VERSION 5.8 ;
BUSBITCHARS "[]" ;
DIVIDERCHAR "/" ;

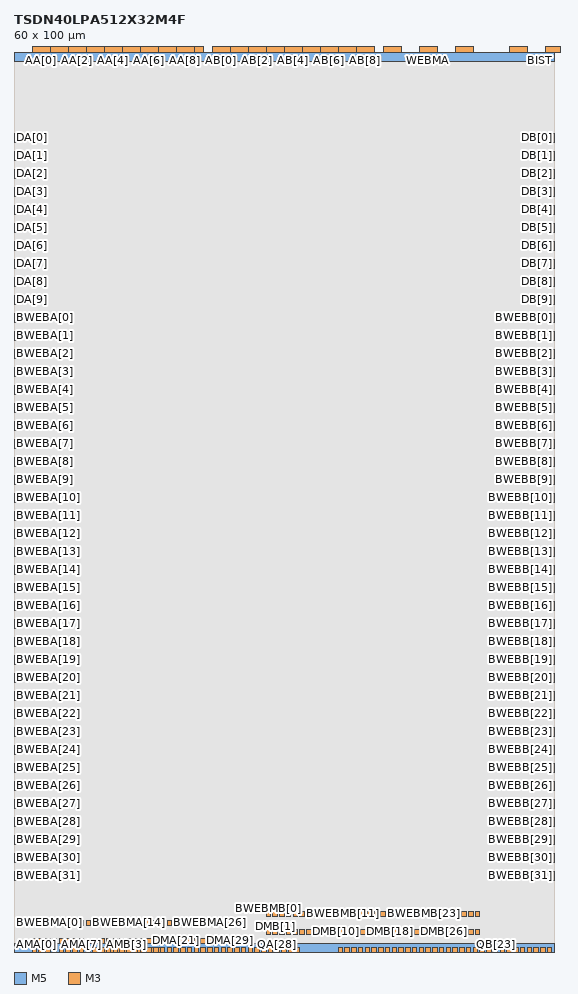
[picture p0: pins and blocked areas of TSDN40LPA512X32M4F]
MACRO TSDN40LPA512X32M4F
  CLASS BLOCK ;
  ORIGIN 0 0 ;
  SIZE 60.0 BY 100.0 ;        # TODO: pick conservative size (microns)
  SITE core ;                 # TODO: stdcell site name from your PDK
  SYMMETRY X Y ;

  # ------- Power/Ground pins (required) -------
  PIN VDD
    DIRECTION INOUT ; USE POWER ;
    PORT
      LAYER M5 ;               # TODO: PG routing layer
        RECT 0 99 60 100 ;
    END
  END VDD
  PIN VSS
    DIRECTION INOUT ; USE GROUND ;
    PORT
      LAYER M5 ;
        RECT 0 0 60 1 ;
    END
  END VSS

  # ------- Scalar control/clock pins (examples packed along the north edge) -------
  PIN CLKA  DIRECTION INPUT ; USE SIGNAL ;
    PORT LAYER M3 ; RECT  5 100  7 102 ; END
  END CLKA
  PIN CLKB  DIRECTION INPUT ; USE SIGNAL ;
    PORT LAYER M3 ; RECT  9 100 11 102 ; END
  END CLKB
  PIN CLKM  DIRECTION INPUT ; USE SIGNAL ;
    PORT LAYER M3 ; RECT 13 100 15 102 ; END
  END CLKM

  PIN CEBA  DIRECTION INPUT ; USE SIGNAL ;
    PORT LAYER M3 ; RECT 19 100 21 102 ; END
  END CEBA
  PIN CEBB  DIRECTION INPUT ; USE SIGNAL ;
    PORT LAYER M3 ; RECT 23 100 25 102 ; END
  END CEBB
  PIN CEBMA DIRECTION INPUT ; USE SIGNAL ;
    PORT LAYER M3 ; RECT 27 100 29 102 ; END
  END CEBMA
  PIN CEBMB DIRECTION INPUT ; USE SIGNAL ;
    PORT LAYER M3 ; RECT 31 100 33 102 ; END
  END CEBMB

  PIN WEBA  DIRECTION INPUT ; USE SIGNAL ;
    PORT LAYER M3 ; RECT 37 100 39 102 ; END
  END WEBA
  PIN WEBB  DIRECTION INPUT ; USE SIGNAL ;
    PORT LAYER M3 ; RECT 41 100 43 102 ; END
  END WEBB
  PIN WEBMA DIRECTION INPUT ; USE SIGNAL ;
    PORT LAYER M3 ; RECT 45 100 47 102 ; END
  END WEBMA
  PIN WEBMB DIRECTION INPUT ; USE SIGNAL ;
    PORT LAYER M3 ; RECT 49 100 51 102 ; END
  END WEBMB

  PIN PD    DIRECTION INPUT ; USE SIGNAL ;
    PORT LAYER M3 ; RECT 55 100 57 102 ; END
  END PD
  PIN BIST  DIRECTION INPUT ; USE SIGNAL ;
    PORT LAYER M3 ; RECT 59 100 61 102 ; END
  END BIST

  # Address A: AA[8:0]
  PIN AA[0] DIRECTION INPUT ;  PORT LAYER M3 ; RECT  2 100  4 102 ; END  END AA[0]
  PIN AA[1] DIRECTION INPUT ;  PORT LAYER M3 ; RECT  4 100  6 102 ; END  END AA[1]
  PIN AA[2] DIRECTION INPUT ;  PORT LAYER M3 ; RECT  6 100  8 102 ; END  END AA[2]
  PIN AA[3] DIRECTION INPUT ;  PORT LAYER M3 ; RECT  8 100 10 102 ; END  END AA[3]
  PIN AA[4] DIRECTION INPUT ;  PORT LAYER M3 ; RECT 10 100 12 102 ; END  END AA[4]
  PIN AA[5] DIRECTION INPUT ;  PORT LAYER M3 ; RECT 12 100 14 102 ; END  END AA[5]
  PIN AA[6] DIRECTION INPUT ;  PORT LAYER M3 ; RECT 14 100 16 102 ; END  END AA[6]
  PIN AA[7] DIRECTION INPUT ;  PORT LAYER M3 ; RECT 16 100 18 102 ; END  END AA[7]
  PIN AA[8] DIRECTION INPUT ;  PORT LAYER M3 ; RECT 18 100 20 102 ; END  END AA[8]

  # Address B: AB[8:0]
  PIN AB[0] DIRECTION INPUT ;  PORT LAYER M3 ; RECT 22 100 24 102 ; END  END AB[0]
  PIN AB[1] DIRECTION INPUT ;  PORT LAYER M3 ; RECT 24 100 26 102 ; END  END AB[1]
  PIN AB[2] DIRECTION INPUT ;  PORT LAYER M3 ; RECT 26 100 28 102 ; END  END AB[2]
  PIN AB[3] DIRECTION INPUT ;  PORT LAYER M3 ; RECT 28 100 30 102 ; END  END AB[3]
  PIN AB[4] DIRECTION INPUT ;  PORT LAYER M3 ; RECT 30 100 32 102 ; END  END AB[4]
  PIN AB[5] DIRECTION INPUT ;  PORT LAYER M3 ; RECT 32 100 34 102 ; END  END AB[5]
  PIN AB[6] DIRECTION INPUT ;  PORT LAYER M3 ; RECT 34 100 36 102 ; END  END AB[6]
  PIN AB[7] DIRECTION INPUT ;  PORT LAYER M3 ; RECT 36 100 38 102 ; END  END AB[7]
  PIN AB[8] DIRECTION INPUT ;  PORT LAYER M3 ; RECT 38 100 40 102 ; END  END AB[8]

  # Put DA along west edge, DB along east edge (example)
  PIN DA[0] DIRECTION INPUT ; USE SIGNAL ;
    PORT LAYER M3 ; RECT 0.0 90.0 0.5 91.0 ; END
  END DA[0]

  PIN DA[1] DIRECTION INPUT ; USE SIGNAL ;
    PORT LAYER M3 ; RECT 0.0 88.0 0.5 89.0 ; END
  END DA[1]

  PIN DA[2] DIRECTION INPUT ; USE SIGNAL ;
    PORT LAYER M3 ; RECT 0.0 86.0 0.5 87.0 ; END
  END DA[2]

  PIN DA[3] DIRECTION INPUT ; USE SIGNAL ;
    PORT LAYER M3 ; RECT 0.0 84.0 0.5 85.0 ; END
  END DA[3]

  PIN DA[4] DIRECTION INPUT ; USE SIGNAL ;
    PORT LAYER M3 ; RECT 0.0 82.0 0.5 83.0 ; END
  END DA[4]

  PIN DA[5] DIRECTION INPUT ; USE SIGNAL ;
    PORT LAYER M3 ; RECT 0.0 80.0 0.5 81.0 ; END
  END DA[5]

  PIN DA[6] DIRECTION INPUT ; USE SIGNAL ;
    PORT LAYER M3 ; RECT 0.0 78.0 0.5 79.0 ; END
  END DA[6]

  PIN DA[7] DIRECTION INPUT ; USE SIGNAL ;
    PORT LAYER M3 ; RECT 0.0 76.0 0.5 77.0 ; END
  END DA[7]

  PIN DA[8] DIRECTION INPUT ; USE SIGNAL ;
    PORT LAYER M3 ; RECT 0.0 74.0 0.5 75.0 ; END
  END DA[8]

  PIN DA[9] DIRECTION INPUT ; USE SIGNAL ;
    PORT LAYER M3 ; RECT 0.0 72.0 0.5 73.0 ; END
  END DA[9]

  PIN DA[10] DIRECTION INPUT ; USE SIGNAL ;
    PORT LAYER M3 ; RECT 0.0 70.0 0.5 71.0 ; END
  END DA[10]

  PIN DA[11] DIRECTION INPUT ; USE SIGNAL ;
    PORT LAYER M3 ; RECT 0.0 68.0 0.5 69.0 ; END
  END DA[11]

  PIN DA[12] DIRECTION INPUT ; USE SIGNAL ;
    PORT LAYER M3 ; RECT 0.0 66.0 0.5 67.0 ; END
  END DA[12]

  PIN DA[13] DIRECTION INPUT ; USE SIGNAL ;
    PORT LAYER M3 ; RECT 0.0 64.0 0.5 65.0 ; END
  END DA[13]

  PIN DA[14] DIRECTION INPUT ; USE SIGNAL ;
    PORT LAYER M3 ; RECT 0.0 62.0 0.5 63.0 ; END
  END DA[14]

  PIN DA[15] DIRECTION INPUT ; USE SIGNAL ;
    PORT LAYER M3 ; RECT 0.0 60.0 0.5 61.0 ; END
  END DA[15]

  PIN DA[16] DIRECTION INPUT ; USE SIGNAL ;
    PORT LAYER M3 ; RECT 0.0 58.0 0.5 59.0 ; END
  END DA[16]

  PIN DA[17] DIRECTION INPUT ; USE SIGNAL ;
    PORT LAYER M3 ; RECT 0.0 56.0 0.5 57.0 ; END
  END DA[17]

  PIN DA[18] DIRECTION INPUT ; USE SIGNAL ;
    PORT LAYER M3 ; RECT 0.0 54.0 0.5 55.0 ; END
  END DA[18]

  PIN DA[19] DIRECTION INPUT ; USE SIGNAL ;
    PORT LAYER M3 ; RECT 0.0 52.0 0.5 53.0 ; END
  END DA[19]

  PIN DA[20] DIRECTION INPUT ; USE SIGNAL ;
    PORT LAYER M3 ; RECT 0.0 50.0 0.5 51.0 ; END
  END DA[20]

  PIN DA[21] DIRECTION INPUT ; USE SIGNAL ;
    PORT LAYER M3 ; RECT 0.0 48.0 0.5 49.0 ; END
  END DA[21]

  PIN DA[22] DIRECTION INPUT ; USE SIGNAL ;
    PORT LAYER M3 ; RECT 0.0 46.0 0.5 47.0 ; END
  END DA[22]

  PIN DA[23] DIRECTION INPUT ; USE SIGNAL ;
    PORT LAYER M3 ; RECT 0.0 44.0 0.5 45.0 ; END
  END DA[23]

  PIN DA[24] DIRECTION INPUT ; USE SIGNAL ;
    PORT LAYER M3 ; RECT 0.0 42.0 0.5 43.0 ; END
  END DA[24]

  PIN DA[25] DIRECTION INPUT ; USE SIGNAL ;
    PORT LAYER M3 ; RECT 0.0 40.0 0.5 41.0 ; END
  END DA[25]

  PIN DA[26] DIRECTION INPUT ; USE SIGNAL ;
    PORT LAYER M3 ; RECT 0.0 38.0 0.5 39.0 ; END
  END DA[26]

  PIN DA[27] DIRECTION INPUT ; USE SIGNAL ;
    PORT LAYER M3 ; RECT 0.0 36.0 0.5 37.0 ; END
  END DA[27]

  PIN DA[28] DIRECTION INPUT ; USE SIGNAL ;
    PORT LAYER M3 ; RECT 0.0 34.0 0.5 35.0 ; END
  END DA[28]

  PIN DA[29] DIRECTION INPUT ; USE SIGNAL ;
    PORT LAYER M3 ; RECT 0.0 32.0 0.5 33.0 ; END
  END DA[29]

  PIN DA[30] DIRECTION INPUT ; USE SIGNAL ;
    PORT LAYER M3 ; RECT 0.0 30.0 0.5 31.0 ; END
  END DA[30]

  PIN DA[31] DIRECTION INPUT ; USE SIGNAL ;
    PORT LAYER M3 ; RECT 0.0 28.0 0.5 29.0 ; END
  END DA[31]

  # Data bus B inputs (DB[31:0]) on east edge
  PIN DB[0]  DIRECTION INPUT ; USE SIGNAL ;
    PORT LAYER M3 ; RECT 59.5 90.0 60.0 91.0 ; END
  END DB[0]

  PIN DB[1]  DIRECTION INPUT ; USE SIGNAL ;
    PORT LAYER M3 ; RECT 59.5 88.0 60.0 89.0 ; END
  END DB[1]

  PIN DB[2]  DIRECTION INPUT ; USE SIGNAL ;
    PORT LAYER M3 ; RECT 59.5 86.0 60.0 87.0 ; END
  END DB[2]

  PIN DB[3]  DIRECTION INPUT ; USE SIGNAL ;
    PORT LAYER M3 ; RECT 59.5 84.0 60.0 85.0 ; END
  END DB[3]

  PIN DB[4]  DIRECTION INPUT ; USE SIGNAL ;
    PORT LAYER M3 ; RECT 59.5 82.0 60.0 83.0 ; END
  END DB[4]

  PIN DB[5]  DIRECTION INPUT ; USE SIGNAL ;
    PORT LAYER M3 ; RECT 59.5 80.0 60.0 81.0 ; END
  END DB[5]

  PIN DB[6]  DIRECTION INPUT ; USE SIGNAL ;
    PORT LAYER M3 ; RECT 59.5 78.0 60.0 79.0 ; END
  END DB[6]

  PIN DB[7]  DIRECTION INPUT ; USE SIGNAL ;
    PORT LAYER M3 ; RECT 59.5 76.0 60.0 77.0 ; END
  END DB[7]

  PIN DB[8]  DIRECTION INPUT ; USE SIGNAL ;
    PORT LAYER M3 ; RECT 59.5 74.0 60.0 75.0 ; END
  END DB[8]

  PIN DB[9]  DIRECTION INPUT ; USE SIGNAL ;
    PORT LAYER M3 ; RECT 59.5 72.0 60.0 73.0 ; END
  END DB[9]

  PIN DB[10] DIRECTION INPUT ; USE SIGNAL ;
    PORT LAYER M3 ; RECT 59.5 70.0 60.0 71.0 ; END
  END DB[10]

  PIN DB[11] DIRECTION INPUT ; USE SIGNAL ;
    PORT LAYER M3 ; RECT 59.5 68.0 60.0 69.0 ; END
  END DB[11]

  PIN DB[12] DIRECTION INPUT ; USE SIGNAL ;
    PORT LAYER M3 ; RECT 59.5 66.0 60.0 67.0 ; END
  END DB[12]

  PIN DB[13] DIRECTION INPUT ; USE SIGNAL ;
    PORT LAYER M3 ; RECT 59.5 64.0 60.0 65.0 ; END
  END DB[13]

  PIN DB[14] DIRECTION INPUT ; USE SIGNAL ;
    PORT LAYER M3 ; RECT 59.5 62.0 60.0 63.0 ; END
  END DB[14]

  PIN DB[15] DIRECTION INPUT ; USE SIGNAL ;
    PORT LAYER M3 ; RECT 59.5 60.0 60.0 61.0 ; END
  END DB[15]

  PIN DB[16] DIRECTION INPUT ; USE SIGNAL ;
    PORT LAYER M3 ; RECT 59.5 58.0 60.0 59.0 ; END
  END DB[16]

  PIN DB[17] DIRECTION INPUT ; USE SIGNAL ;
    PORT LAYER M3 ; RECT 59.5 56.0 60.0 57.0 ; END
  END DB[17]

  PIN DB[18] DIRECTION INPUT ; USE SIGNAL ;
    PORT LAYER M3 ; RECT 59.5 54.0 60.0 55.0 ; END
  END DB[18]

  PIN DB[19] DIRECTION INPUT ; USE SIGNAL ;
    PORT LAYER M3 ; RECT 59.5 52.0 60.0 53.0 ; END
  END DB[19]

  PIN DB[20] DIRECTION INPUT ; USE SIGNAL ;
    PORT LAYER M3 ; RECT 59.5 50.0 60.0 51.0 ; END
  END DB[20]

  PIN DB[21] DIRECTION INPUT ; USE SIGNAL ;
    PORT LAYER M3 ; RECT 59.5 48.0 60.0 49.0 ; END
  END DB[21]

  PIN DB[22] DIRECTION INPUT ; USE SIGNAL ;
    PORT LAYER M3 ; RECT 59.5 46.0 60.0 47.0 ; END
  END DB[22]

  PIN DB[23] DIRECTION INPUT ; USE SIGNAL ;
    PORT LAYER M3 ; RECT 59.5 44.0 60.0 45.0 ; END
  END DB[23]

  PIN DB[24] DIRECTION INPUT ; USE SIGNAL ;
    PORT LAYER M3 ; RECT 59.5 42.0 60.0 43.0 ; END
  END DB[24]

  PIN DB[25] DIRECTION INPUT ; USE SIGNAL ;
    PORT LAYER M3 ; RECT 59.5 40.0 60.0 41.0 ; END
  END DB[25]

  PIN DB[26] DIRECTION INPUT ; USE SIGNAL ;
    PORT LAYER M3 ; RECT 59.5 38.0 60.0 39.0 ; END
  END DB[26]

  PIN DB[27] DIRECTION INPUT ; USE SIGNAL ;
    PORT LAYER M3 ; RECT 59.5 36.0 60.0 37.0 ; END
  END DB[27]

  PIN DB[28] DIRECTION INPUT ; USE SIGNAL ;
    PORT LAYER M3 ; RECT 59.5 34.0 60.0 35.0 ; END
  END DB[28]

  PIN DB[29] DIRECTION INPUT ; USE SIGNAL ;
    PORT LAYER M3 ; RECT 59.5 32.0 60.0 33.0 ; END
  END DB[29]

  PIN DB[30] DIRECTION INPUT ; USE SIGNAL ;
    PORT LAYER M3 ; RECT 59.5 30.0 60.0 31.0 ; END
  END DB[30]

  PIN DB[31] DIRECTION INPUT ; USE SIGNAL ;
    PORT LAYER M3 ; RECT 59.5 28.0 60.0 29.0 ; END
  END DB[31]

    # Byte Write Enable A inputs (BWEBA[31:0]) on west edge
  PIN BWEBA[0] DIRECTION INPUT ; USE SIGNAL ;
    PORT LAYER M3 ; RECT 0.0 70.0 0.5 71.0 ; END
  END BWEBA[0]

  PIN BWEBA[1] DIRECTION INPUT ; USE SIGNAL ;
    PORT LAYER M3 ; RECT 0.0 68.0 0.5 69.0 ; END
  END BWEBA[1]

  PIN BWEBA[2] DIRECTION INPUT ; USE SIGNAL ;
    PORT LAYER M3 ; RECT 0.0 66.0 0.5 67.0 ; END
  END BWEBA[2]

  PIN BWEBA[3] DIRECTION INPUT ; USE SIGNAL ;
    PORT LAYER M3 ; RECT 0.0 64.0 0.5 65.0 ; END
  END BWEBA[3]

  PIN BWEBA[4] DIRECTION INPUT ; USE SIGNAL ;
    PORT LAYER M3 ; RECT 0.0 62.0 0.5 63.0 ; END
  END BWEBA[4]

  PIN BWEBA[5] DIRECTION INPUT ; USE SIGNAL ;
    PORT LAYER M3 ; RECT 0.0 60.0 0.5 61.0 ; END
  END BWEBA[5]

  PIN BWEBA[6] DIRECTION INPUT ; USE SIGNAL ;
    PORT LAYER M3 ; RECT 0.0 58.0 0.5 59.0 ; END
  END BWEBA[6]

  PIN BWEBA[7] DIRECTION INPUT ; USE SIGNAL ;
    PORT LAYER M3 ; RECT 0.0 56.0 0.5 57.0 ; END
  END BWEBA[7]

  PIN BWEBA[8] DIRECTION INPUT ; USE SIGNAL ;
    PORT LAYER M3 ; RECT 0.0 54.0 0.5 55.0 ; END
  END BWEBA[8]

  PIN BWEBA[9] DIRECTION INPUT ; USE SIGNAL ;
    PORT LAYER M3 ; RECT 0.0 52.0 0.5 53.0 ; END
  END BWEBA[9]

  PIN BWEBA[10] DIRECTION INPUT ; USE SIGNAL ;
    PORT LAYER M3 ; RECT 0.0 50.0 0.5 51.0 ; END
  END BWEBA[10]

  PIN BWEBA[11] DIRECTION INPUT ; USE SIGNAL ;
    PORT LAYER M3 ; RECT 0.0 48.0 0.5 49.0 ; END
  END BWEBA[11]

  PIN BWEBA[12] DIRECTION INPUT ; USE SIGNAL ;
    PORT LAYER M3 ; RECT 0.0 46.0 0.5 47.0 ; END
  END BWEBA[12]

  PIN BWEBA[13] DIRECTION INPUT ; USE SIGNAL ;
    PORT LAYER M3 ; RECT 0.0 44.0 0.5 45.0 ; END
  END BWEBA[13]

  PIN BWEBA[14] DIRECTION INPUT ; USE SIGNAL ;
    PORT LAYER M3 ; RECT 0.0 42.0 0.5 43.0 ; END
  END BWEBA[14]

  PIN BWEBA[15] DIRECTION INPUT ; USE SIGNAL ;
    PORT LAYER M3 ; RECT 0.0 40.0 0.5 41.0 ; END
  END BWEBA[15]

  PIN BWEBA[16] DIRECTION INPUT ; USE SIGNAL ;
    PORT LAYER M3 ; RECT 0.0 38.0 0.5 39.0 ; END
  END BWEBA[16]

  PIN BWEBA[17] DIRECTION INPUT ; USE SIGNAL ;
    PORT LAYER M3 ; RECT 0.0 36.0 0.5 37.0 ; END
  END BWEBA[17]

  PIN BWEBA[18] DIRECTION INPUT ; USE SIGNAL ;
    PORT LAYER M3 ; RECT 0.0 34.0 0.5 35.0 ; END
  END BWEBA[18]

  PIN BWEBA[19] DIRECTION INPUT ; USE SIGNAL ;
    PORT LAYER M3 ; RECT 0.0 32.0 0.5 33.0 ; END
  END BWEBA[19]

  PIN BWEBA[20] DIRECTION INPUT ; USE SIGNAL ;
    PORT LAYER M3 ; RECT 0.0 30.0 0.5 31.0 ; END
  END BWEBA[20]

  PIN BWEBA[21] DIRECTION INPUT ; USE SIGNAL ;
    PORT LAYER M3 ; RECT 0.0 28.0 0.5 29.0 ; END
  END BWEBA[21]

  PIN BWEBA[22] DIRECTION INPUT ; USE SIGNAL ;
    PORT LAYER M3 ; RECT 0.0 26.0 0.5 27.0 ; END
  END BWEBA[22]

  PIN BWEBA[23] DIRECTION INPUT ; USE SIGNAL ;
    PORT LAYER M3 ; RECT 0.0 24.0 0.5 25.0 ; END
  END BWEBA[23]

  PIN BWEBA[24] DIRECTION INPUT ; USE SIGNAL ;
    PORT LAYER M3 ; RECT 0.0 22.0 0.5 23.0 ; END
  END BWEBA[24]

  PIN BWEBA[25] DIRECTION INPUT ; USE SIGNAL ;
    PORT LAYER M3 ; RECT 0.0 20.0 0.5 21.0 ; END
  END BWEBA[25]

  PIN BWEBA[26] DIRECTION INPUT ; USE SIGNAL ;
    PORT LAYER M3 ; RECT 0.0 18.0 0.5 19.0 ; END
  END BWEBA[26]

  PIN BWEBA[27] DIRECTION INPUT ; USE SIGNAL ;
    PORT LAYER M3 ; RECT 0.0 16.0 0.5 17.0 ; END
  END BWEBA[27]

  PIN BWEBA[28] DIRECTION INPUT ; USE SIGNAL ;
    PORT LAYER M3 ; RECT 0.0 14.0 0.5 15.0 ; END
  END BWEBA[28]

  PIN BWEBA[29] DIRECTION INPUT ; USE SIGNAL ;
    PORT LAYER M3 ; RECT 0.0 12.0 0.5 13.0 ; END
  END BWEBA[29]

  PIN BWEBA[30] DIRECTION INPUT ; USE SIGNAL ;
    PORT LAYER M3 ; RECT 0.0 10.0 0.5 11.0 ; END
  END BWEBA[30]

  PIN BWEBA[31] DIRECTION INPUT ; USE SIGNAL ;
    PORT LAYER M3 ; RECT 0.0 8.0 0.5 9.0 ; END
  END BWEBA[31]

  # Byte Write Enable B inputs (BWEBB[31:0]) on east edge
  PIN BWEBB[0]  DIRECTION INPUT ; USE SIGNAL ;
    PORT LAYER M3 ; RECT 59.5 70.0 60.0 71.0 ; END
  END BWEBB[0]

  PIN BWEBB[1]  DIRECTION INPUT ; USE SIGNAL ;
    PORT LAYER M3 ; RECT 59.5 68.0 60.0 69.0 ; END
  END BWEBB[1]

  PIN BWEBB[2]  DIRECTION INPUT ; USE SIGNAL ;
    PORT LAYER M3 ; RECT 59.5 66.0 60.0 67.0 ; END
  END BWEBB[2]

  PIN BWEBB[3]  DIRECTION INPUT ; USE SIGNAL ;
    PORT LAYER M3 ; RECT 59.5 64.0 60.0 65.0 ; END
  END BWEBB[3]

  PIN BWEBB[4]  DIRECTION INPUT ; USE SIGNAL ;
    PORT LAYER M3 ; RECT 59.5 62.0 60.0 63.0 ; END
  END BWEBB[4]

  PIN BWEBB[5]  DIRECTION INPUT ; USE SIGNAL ;
    PORT LAYER M3 ; RECT 59.5 60.0 60.0 61.0 ; END
  END BWEBB[5]

  PIN BWEBB[6]  DIRECTION INPUT ; USE SIGNAL ;
    PORT LAYER M3 ; RECT 59.5 58.0 60.0 59.0 ; END
  END BWEBB[6]

  PIN BWEBB[7]  DIRECTION INPUT ; USE SIGNAL ;
    PORT LAYER M3 ; RECT 59.5 56.0 60.0 57.0 ; END
  END BWEBB[7]

  PIN BWEBB[8]  DIRECTION INPUT ; USE SIGNAL ;
    PORT LAYER M3 ; RECT 59.5 54.0 60.0 55.0 ; END
  END BWEBB[8]

  PIN BWEBB[9]  DIRECTION INPUT ; USE SIGNAL ;
    PORT LAYER M3 ; RECT 59.5 52.0 60.0 53.0 ; END
  END BWEBB[9]

  PIN BWEBB[10] DIRECTION INPUT ; USE SIGNAL ;
    PORT LAYER M3 ; RECT 59.5 50.0 60.0 51.0 ; END
  END BWEBB[10]

  PIN BWEBB[11] DIRECTION INPUT ; USE SIGNAL ;
    PORT LAYER M3 ; RECT 59.5 48.0 60.0 49.0 ; END
  END BWEBB[11]

  PIN BWEBB[12] DIRECTION INPUT ; USE SIGNAL ;
    PORT LAYER M3 ; RECT 59.5 46.0 60.0 47.0 ; END
  END BWEBB[12]

  PIN BWEBB[13] DIRECTION INPUT ; USE SIGNAL ;
    PORT LAYER M3 ; RECT 59.5 44.0 60.0 45.0 ; END
  END BWEBB[13]

  PIN BWEBB[14] DIRECTION INPUT ; USE SIGNAL ;
    PORT LAYER M3 ; RECT 59.5 42.0 60.0 43.0 ; END
  END BWEBB[14]

  PIN BWEBB[15] DIRECTION INPUT ; USE SIGNAL ;
    PORT LAYER M3 ; RECT 59.5 40.0 60.0 41.0 ; END
  END BWEBB[15]

  PIN BWEBB[16] DIRECTION INPUT ; USE SIGNAL ;
    PORT LAYER M3 ; RECT 59.5 38.0 60.0 39.0 ; END
  END BWEBB[16]

  PIN BWEBB[17] DIRECTION INPUT ; USE SIGNAL ;
    PORT LAYER M3 ; RECT 59.5 36.0 60.0 37.0 ; END
  END BWEBB[17]

  PIN BWEBB[18] DIRECTION INPUT ; USE SIGNAL ;
    PORT LAYER M3 ; RECT 59.5 34.0 60.0 35.0 ; END
  END BWEBB[18]

  PIN BWEBB[19] DIRECTION INPUT ; USE SIGNAL ;
    PORT LAYER M3 ; RECT 59.5 32.0 60.0 33.0 ; END
  END BWEBB[19]

  PIN BWEBB[20] DIRECTION INPUT ; USE SIGNAL ;
    PORT LAYER M3 ; RECT 59.5 30.0 60.0 31.0 ; END
  END BWEBB[20]

  PIN BWEBB[21] DIRECTION INPUT ; USE SIGNAL ;
    PORT LAYER M3 ; RECT 59.5 28.0 60.0 29.0 ; END
  END BWEBB[21]

  PIN BWEBB[22] DIRECTION INPUT ; USE SIGNAL ;
    PORT LAYER M3 ; RECT 59.5 26.0 60.0 27.0 ; END
  END BWEBB[22]

  PIN BWEBB[23] DIRECTION INPUT ; USE SIGNAL ;
    PORT LAYER M3 ; RECT 59.5 24.0 60.0 25.0 ; END
  END BWEBB[23]

  PIN BWEBB[24] DIRECTION INPUT ; USE SIGNAL ;
    PORT LAYER M3 ; RECT 59.5 22.0 60.0 23.0 ; END
  END BWEBB[24]

  PIN BWEBB[25] DIRECTION INPUT ; USE SIGNAL ;
    PORT LAYER M3 ; RECT 59.5 20.0 60.0 21.0 ; END
  END BWEBB[25]

  PIN BWEBB[26] DIRECTION INPUT ; USE SIGNAL ;
    PORT LAYER M3 ; RECT 59.5 18.0 60.0 19.0 ; END
  END BWEBB[26]

  PIN BWEBB[27] DIRECTION INPUT ; USE SIGNAL ;
    PORT LAYER M3 ; RECT 59.5 16.0 60.0 17.0 ; END
  END BWEBB[27]

  PIN BWEBB[28] DIRECTION INPUT ; USE SIGNAL ;
    PORT LAYER M3 ; RECT 59.5 14.0 60.0 15.0 ; END
  END BWEBB[28]

  PIN BWEBB[29] DIRECTION INPUT ; USE SIGNAL ;
    PORT LAYER M3 ; RECT 59.5 12.0 60.0 13.0 ; END
  END BWEBB[29]

  PIN BWEBB[30] DIRECTION INPUT ; USE SIGNAL ;
    PORT LAYER M3 ; RECT 59.5 10.0 60.0 11.0 ; END
  END BWEBB[30]

  PIN BWEBB[31] DIRECTION INPUT ; USE SIGNAL ;
    PORT LAYER M3 ; RECT 59.5 8.0 60.0 9.0 ; END
  END BWEBB[31]

  # Address bus AMA[8:0] on south edge
  PIN AMA[0] DIRECTION INPUT ; USE SIGNAL ;
    PORT LAYER M3 ; RECT  2.00 0.00  2.50 0.50 ; END
  END AMA[0]

  PIN AMA[1] DIRECTION INPUT ; USE SIGNAL ;
    PORT LAYER M3 ; RECT  2.75 0.00  3.25 0.50 ; END
  END AMA[1]

  PIN AMA[2] DIRECTION INPUT ; USE SIGNAL ;
    PORT LAYER M3 ; RECT  3.50 0.00  4.00 0.50 ; END
  END AMA[2]

  PIN AMA[3] DIRECTION INPUT ; USE SIGNAL ;
    PORT LAYER M3 ; RECT  4.25 0.00  4.75 0.50 ; END
  END AMA[3]

  PIN AMA[4] DIRECTION INPUT ; USE SIGNAL ;
    PORT LAYER M3 ; RECT  5.00 0.00  5.50 0.50 ; END
  END AMA[4]

  PIN AMA[5] DIRECTION INPUT ; USE SIGNAL ;
    PORT LAYER M3 ; RECT  5.75 0.00  6.25 0.50 ; END
  END AMA[5]

  PIN AMA[6] DIRECTION INPUT ; USE SIGNAL ;
    PORT LAYER M3 ; RECT  6.50 0.00  7.00 0.50 ; END
  END AMA[6]

  PIN AMA[7] DIRECTION INPUT ; USE SIGNAL ;
    PORT LAYER M3 ; RECT  7.25 0.00  7.75 0.50 ; END
  END AMA[7]

  PIN AMA[8] DIRECTION INPUT ; USE SIGNAL ;
    PORT LAYER M3 ; RECT  8.00 0.00  8.50 0.50 ; END
  END AMA[8]

  # Address bus AMB[8:0] on south edge
  PIN AMB[0] DIRECTION INPUT ; USE SIGNAL ;
    PORT LAYER M3 ; RECT 10.00 0.00 10.50 0.50 ; END
  END AMB[0]

  PIN AMB[1] DIRECTION INPUT ; USE SIGNAL ;
    PORT LAYER M3 ; RECT 10.75 0.00 11.25 0.50 ; END
  END AMB[1]

  PIN AMB[2] DIRECTION INPUT ; USE SIGNAL ;
    PORT LAYER M3 ; RECT 11.50 0.00 12.00 0.50 ; END
  END AMB[2]

  PIN AMB[3] DIRECTION INPUT ; USE SIGNAL ;
    PORT LAYER M3 ; RECT 12.25 0.00 12.75 0.50 ; END
  END AMB[3]

  PIN AMB[4] DIRECTION INPUT ; USE SIGNAL ;
    PORT LAYER M3 ; RECT 13.00 0.00 13.50 0.50 ; END
  END AMB[4]

  PIN AMB[5] DIRECTION INPUT ; USE SIGNAL ;
    PORT LAYER M3 ; RECT 13.75 0.00 14.25 0.50 ; END
  END AMB[5]

  PIN AMB[6] DIRECTION INPUT ; USE SIGNAL ;
    PORT LAYER M3 ; RECT 14.50 0.00 15.00 0.50 ; END
  END AMB[6]

  PIN AMB[7] DIRECTION INPUT ; USE SIGNAL ;
    PORT LAYER M3 ; RECT 15.25 0.00 15.75 0.50 ; END
  END AMB[7]

  PIN AMB[8] DIRECTION INPUT ; USE SIGNAL ;
    PORT LAYER M3 ; RECT 16.00 0.00 16.50 0.50 ; END
  END AMB[8]

  # DMA[31:0] on south side (y=1.00–1.50), starting x=2.00, step 0.75
  PIN DMA[0]  DIRECTION INPUT ; USE SIGNAL ;  PORT LAYER M3 ; RECT  2.00 1.00  2.50 1.50 ; END  END DMA[0]
  PIN DMA[1]  DIRECTION INPUT ; USE SIGNAL ;  PORT LAYER M3 ; RECT  2.75 1.00  3.25 1.50 ; END  END DMA[1]
  PIN DMA[2]  DIRECTION INPUT ; USE SIGNAL ;  PORT LAYER M3 ; RECT  3.50 1.00  4.00 1.50 ; END  END DMA[2]
  PIN DMA[3]  DIRECTION INPUT ; USE SIGNAL ;  PORT LAYER M3 ; RECT  4.25 1.00  4.75 1.50 ; END  END DMA[3]
  PIN DMA[4]  DIRECTION INPUT ; USE SIGNAL ;  PORT LAYER M3 ; RECT  5.00 1.00  5.50 1.50 ; END  END DMA[4]
  PIN DMA[5]  DIRECTION INPUT ; USE SIGNAL ;  PORT LAYER M3 ; RECT  5.75 1.00  6.25 1.50 ; END  END DMA[5]
  PIN DMA[6]  DIRECTION INPUT ; USE SIGNAL ;  PORT LAYER M3 ; RECT  6.50 1.00  7.00 1.50 ; END  END DMA[6]
  PIN DMA[7]  DIRECTION INPUT ; USE SIGNAL ;  PORT LAYER M3 ; RECT  7.25 1.00  7.75 1.50 ; END  END DMA[7]
  PIN DMA[8]  DIRECTION INPUT ; USE SIGNAL ;  PORT LAYER M3 ; RECT  8.00 1.00  8.50 1.50 ; END  END DMA[8]
  PIN DMA[9]  DIRECTION INPUT ; USE SIGNAL ;  PORT LAYER M3 ; RECT  8.75 1.00  9.25 1.50 ; END  END DMA[9]
  PIN DMA[10] DIRECTION INPUT ; USE SIGNAL ;  PORT LAYER M3 ; RECT  9.50 1.00 10.00 1.50 ; END  END DMA[10]
  PIN DMA[11] DIRECTION INPUT ; USE SIGNAL ;  PORT LAYER M3 ; RECT 10.25 1.00 10.75 1.50 ; END  END DMA[11]
  PIN DMA[12] DIRECTION INPUT ; USE SIGNAL ;  PORT LAYER M3 ; RECT 11.00 1.00 11.50 1.50 ; END  END DMA[12]
  PIN DMA[13] DIRECTION INPUT ; USE SIGNAL ;  PORT LAYER M3 ; RECT 11.75 1.00 12.25 1.50 ; END  END DMA[13]
  PIN DMA[14] DIRECTION INPUT ; USE SIGNAL ;  PORT LAYER M3 ; RECT 12.50 1.00 13.00 1.50 ; END  END DMA[14]
  PIN DMA[15] DIRECTION INPUT ; USE SIGNAL ;  PORT LAYER M3 ; RECT 13.25 1.00 13.75 1.50 ; END  END DMA[15]
  PIN DMA[16] DIRECTION INPUT ; USE SIGNAL ;  PORT LAYER M3 ; RECT 14.00 1.00 14.50 1.50 ; END  END DMA[16]
  PIN DMA[17] DIRECTION INPUT ; USE SIGNAL ;  PORT LAYER M3 ; RECT 14.75 1.00 15.25 1.50 ; END  END DMA[17]
  PIN DMA[18] DIRECTION INPUT ; USE SIGNAL ;  PORT LAYER M3 ; RECT 15.50 1.00 16.00 1.50 ; END  END DMA[18]
  PIN DMA[19] DIRECTION INPUT ; USE SIGNAL ;  PORT LAYER M3 ; RECT 16.25 1.00 16.75 1.50 ; END  END DMA[19]
  PIN DMA[20] DIRECTION INPUT ; USE SIGNAL ;  PORT LAYER M3 ; RECT 17.00 1.00 17.50 1.50 ; END  END DMA[20]
  PIN DMA[21] DIRECTION INPUT ; USE SIGNAL ;  PORT LAYER M3 ; RECT 17.75 1.00 18.25 1.50 ; END  END DMA[21]
  PIN DMA[22] DIRECTION INPUT ; USE SIGNAL ;  PORT LAYER M3 ; RECT 18.50 1.00 19.00 1.50 ; END  END DMA[22]
  PIN DMA[23] DIRECTION INPUT ; USE SIGNAL ;  PORT LAYER M3 ; RECT 19.25 1.00 19.75 1.50 ; END  END DMA[23]
  PIN DMA[24] DIRECTION INPUT ; USE SIGNAL ;  PORT LAYER M3 ; RECT 20.00 1.00 20.50 1.50 ; END  END DMA[24]
  PIN DMA[25] DIRECTION INPUT ; USE SIGNAL ;  PORT LAYER M3 ; RECT 20.75 1.00 21.25 1.50 ; END  END DMA[25]
  PIN DMA[26] DIRECTION INPUT ; USE SIGNAL ;  PORT LAYER M3 ; RECT 21.50 1.00 22.00 1.50 ; END  END DMA[26]
  PIN DMA[27] DIRECTION INPUT ; USE SIGNAL ;  PORT LAYER M3 ; RECT 22.25 1.00 22.75 1.50 ; END  END DMA[27]
  PIN DMA[28] DIRECTION INPUT ; USE SIGNAL ;  PORT LAYER M3 ; RECT 23.00 1.00 23.50 1.50 ; END  END DMA[28]
  PIN DMA[29] DIRECTION INPUT ; USE SIGNAL ;  PORT LAYER M3 ; RECT 23.75 1.00 24.25 1.50 ; END  END DMA[29]
  PIN DMA[30] DIRECTION INPUT ; USE SIGNAL ;  PORT LAYER M3 ; RECT 24.50 1.00 25.00 1.50 ; END  END DMA[30]
  PIN DMA[31] DIRECTION INPUT ; USE SIGNAL ;  PORT LAYER M3 ; RECT 25.25 1.00 25.75 1.50 ; END  END DMA[31]

  # DMB[31:0] on south side (y=2.00–2.50), starting x=28.00, step 0.75
  PIN DMB[0]  DIRECTION INPUT ; USE SIGNAL ;  PORT LAYER M3 ; RECT 28.00 2.00 28.50 2.50 ; END  END DMB[0]
  PIN DMB[1]  DIRECTION INPUT ; USE SIGNAL ;  PORT LAYER M3 ; RECT 28.75 2.00 29.25 2.50 ; END  END DMB[1]
  PIN DMB[2]  DIRECTION INPUT ; USE SIGNAL ;  PORT LAYER M3 ; RECT 29.50 2.00 30.00 2.50 ; END  END DMB[2]
  PIN DMB[3]  DIRECTION INPUT ; USE SIGNAL ;  PORT LAYER M3 ; RECT 30.25 2.00 30.75 2.50 ; END  END DMB[3]
  PIN DMB[4]  DIRECTION INPUT ; USE SIGNAL ;  PORT LAYER M3 ; RECT 31.00 2.00 31.50 2.50 ; END  END DMB[4]
  PIN DMB[5]  DIRECTION INPUT ; USE SIGNAL ;  PORT LAYER M3 ; RECT 31.75 2.00 32.25 2.50 ; END  END DMB[5]
  PIN DMB[6]  DIRECTION INPUT ; USE SIGNAL ;  PORT LAYER M3 ; RECT 32.50 2.00 33.00 2.50 ; END  END DMB[6]
  PIN DMB[7]  DIRECTION INPUT ; USE SIGNAL ;  PORT LAYER M3 ; RECT 33.25 2.00 33.75 2.50 ; END  END DMB[7]
  PIN DMB[8]  DIRECTION INPUT ; USE SIGNAL ;  PORT LAYER M3 ; RECT 34.00 2.00 34.50 2.50 ; END  END DMB[8]
  PIN DMB[9]  DIRECTION INPUT ; USE SIGNAL ;  PORT LAYER M3 ; RECT 34.75 2.00 35.25 2.50 ; END  END DMB[9]
  PIN DMB[10] DIRECTION INPUT ; USE SIGNAL ;  PORT LAYER M3 ; RECT 35.50 2.00 36.00 2.50 ; END  END DMB[10]
  PIN DMB[11] DIRECTION INPUT ; USE SIGNAL ;  PORT LAYER M3 ; RECT 36.25 2.00 36.75 2.50 ; END  END DMB[11]
  PIN DMB[12] DIRECTION INPUT ; USE SIGNAL ;  PORT LAYER M3 ; RECT 37.00 2.00 37.50 2.50 ; END  END DMB[12]
  PIN DMB[13] DIRECTION INPUT ; USE SIGNAL ;  PORT LAYER M3 ; RECT 37.75 2.00 38.25 2.50 ; END  END DMB[13]
  PIN DMB[14] DIRECTION INPUT ; USE SIGNAL ;  PORT LAYER M3 ; RECT 38.50 2.00 39.00 2.50 ; END  END DMB[14]
  PIN DMB[15] DIRECTION INPUT ; USE SIGNAL ;  PORT LAYER M3 ; RECT 39.25 2.00 39.75 2.50 ; END  END DMB[15]
  PIN DMB[16] DIRECTION INPUT ; USE SIGNAL ;  PORT LAYER M3 ; RECT 40.00 2.00 40.50 2.50 ; END  END DMB[16]
  PIN DMB[17] DIRECTION INPUT ; USE SIGNAL ;  PORT LAYER M3 ; RECT 40.75 2.00 41.25 2.50 ; END  END DMB[17]
  PIN DMB[18] DIRECTION INPUT ; USE SIGNAL ;  PORT LAYER M3 ; RECT 41.50 2.00 42.00 2.50 ; END  END DMB[18]
  PIN DMB[19] DIRECTION INPUT ; USE SIGNAL ;  PORT LAYER M3 ; RECT 42.25 2.00 42.75 2.50 ; END  END DMB[19]
  PIN DMB[20] DIRECTION INPUT ; USE SIGNAL ;  PORT LAYER M3 ; RECT 43.00 2.00 43.50 2.50 ; END  END DMB[20]
  PIN DMB[21] DIRECTION INPUT ; USE SIGNAL ;  PORT LAYER M3 ; RECT 43.75 2.00 44.25 2.50 ; END  END DMB[21]
  PIN DMB[22] DIRECTION INPUT ; USE SIGNAL ;  PORT LAYER M3 ; RECT 44.50 2.00 45.00 2.50 ; END  END DMB[22]
  PIN DMB[23] DIRECTION INPUT ; USE SIGNAL ;  PORT LAYER M3 ; RECT 45.25 2.00 45.75 2.50 ; END  END DMB[23]
  PIN DMB[24] DIRECTION INPUT ; USE SIGNAL ;  PORT LAYER M3 ; RECT 46.00 2.00 46.50 2.50 ; END  END DMB[24]
  PIN DMB[25] DIRECTION INPUT ; USE SIGNAL ;  PORT LAYER M3 ; RECT 46.75 2.00 47.25 2.50 ; END  END DMB[25]
  PIN DMB[26] DIRECTION INPUT ; USE SIGNAL ;  PORT LAYER M3 ; RECT 47.50 2.00 48.00 2.50 ; END  END DMB[26]
  PIN DMB[27] DIRECTION INPUT ; USE SIGNAL ;  PORT LAYER M3 ; RECT 48.25 2.00 48.75 2.50 ; END  END DMB[27]
  PIN DMB[28] DIRECTION INPUT ; USE SIGNAL ;  PORT LAYER M3 ; RECT 49.00 2.00 49.50 2.50 ; END  END DMB[28]
  PIN DMB[29] DIRECTION INPUT ; USE SIGNAL ;  PORT LAYER M3 ; RECT 49.75 2.00 50.25 2.50 ; END  END DMB[29]
  PIN DMB[30] DIRECTION INPUT ; USE SIGNAL ;  PORT LAYER M3 ; RECT 50.50 2.00 51.00 2.50 ; END  END DMB[30]
  PIN DMB[31] DIRECTION INPUT ; USE SIGNAL ;  PORT LAYER M3 ; RECT 51.25 2.00 51.75 2.50 ; END  END DMB[31]

  # BWEBMA[31:0] on south side (y=3.00–3.50), starting x=2.00, step 0.75
  PIN BWEBMA[0]  DIRECTION INPUT ; USE SIGNAL ;  PORT LAYER M3 ; RECT  2.00 3.00  2.50 3.50 ; END  END BWEBMA[0]
  PIN BWEBMA[1]  DIRECTION INPUT ; USE SIGNAL ;  PORT LAYER M3 ; RECT  2.75 3.00  3.25 3.50 ; END  END BWEBMA[1]
  PIN BWEBMA[2]  DIRECTION INPUT ; USE SIGNAL ;  PORT LAYER M3 ; RECT  3.50 3.00  4.00 3.50 ; END  END BWEBMA[2]
  PIN BWEBMA[3]  DIRECTION INPUT ; USE SIGNAL ;  PORT LAYER M3 ; RECT  4.25 3.00  4.75 3.50 ; END  END BWEBMA[3]
  PIN BWEBMA[4]  DIRECTION INPUT ; USE SIGNAL ;  PORT LAYER M3 ; RECT  5.00 3.00  5.50 3.50 ; END  END BWEBMA[4]
  PIN BWEBMA[5]  DIRECTION INPUT ; USE SIGNAL ;  PORT LAYER M3 ; RECT  5.75 3.00  6.25 3.50 ; END  END BWEBMA[5]
  PIN BWEBMA[6]  DIRECTION INPUT ; USE SIGNAL ;  PORT LAYER M3 ; RECT  6.50 3.00  7.00 3.50 ; END  END BWEBMA[6]
  PIN BWEBMA[7]  DIRECTION INPUT ; USE SIGNAL ;  PORT LAYER M3 ; RECT  7.25 3.00  7.75 3.50 ; END  END BWEBMA[7]
  PIN BWEBMA[8]  DIRECTION INPUT ; USE SIGNAL ;  PORT LAYER M3 ; RECT  8.00 3.00  8.50 3.50 ; END  END BWEBMA[8]
  PIN BWEBMA[9]  DIRECTION INPUT ; USE SIGNAL ;  PORT LAYER M3 ; RECT  8.75 3.00  9.25 3.50 ; END  END BWEBMA[9]
  PIN BWEBMA[10] DIRECTION INPUT ; USE SIGNAL ;  PORT LAYER M3 ; RECT  9.50 3.00 10.00 3.50 ; END  END BWEBMA[10]
  PIN BWEBMA[11] DIRECTION INPUT ; USE SIGNAL ;  PORT LAYER M3 ; RECT 10.25 3.00 10.75 3.50 ; END  END BWEBMA[11]
  PIN BWEBMA[12] DIRECTION INPUT ; USE SIGNAL ;  PORT LAYER M3 ; RECT 11.00 3.00 11.50 3.50 ; END  END BWEBMA[12]
  PIN BWEBMA[13] DIRECTION INPUT ; USE SIGNAL ;  PORT LAYER M3 ; RECT 11.75 3.00 12.25 3.50 ; END  END BWEBMA[13]
  PIN BWEBMA[14] DIRECTION INPUT ; USE SIGNAL ;  PORT LAYER M3 ; RECT 12.50 3.00 13.00 3.50 ; END  END BWEBMA[14]
  PIN BWEBMA[15] DIRECTION INPUT ; USE SIGNAL ;  PORT LAYER M3 ; RECT 13.25 3.00 13.75 3.50 ; END  END BWEBMA[15]
  PIN BWEBMA[16] DIRECTION INPUT ; USE SIGNAL ;  PORT LAYER M3 ; RECT 14.00 3.00 14.50 3.50 ; END  END BWEBMA[16]
  PIN BWEBMA[17] DIRECTION INPUT ; USE SIGNAL ;  PORT LAYER M3 ; RECT 14.75 3.00 15.25 3.50 ; END  END BWEBMA[17]
  PIN BWEBMA[18] DIRECTION INPUT ; USE SIGNAL ;  PORT LAYER M3 ; RECT 15.50 3.00 16.00 3.50 ; END  END BWEBMA[18]
  PIN BWEBMA[19] DIRECTION INPUT ; USE SIGNAL ;  PORT LAYER M3 ; RECT 16.25 3.00 16.75 3.50 ; END  END BWEBMA[19]
  PIN BWEBMA[20] DIRECTION INPUT ; USE SIGNAL ;  PORT LAYER M3 ; RECT 17.00 3.00 17.50 3.50 ; END  END BWEBMA[20]
  PIN BWEBMA[21] DIRECTION INPUT ; USE SIGNAL ;  PORT LAYER M3 ; RECT 17.75 3.00 18.25 3.50 ; END  END BWEBMA[21]
  PIN BWEBMA[22] DIRECTION INPUT ; USE SIGNAL ;  PORT LAYER M3 ; RECT 18.50 3.00 19.00 3.50 ; END  END BWEBMA[22]
  PIN BWEBMA[23] DIRECTION INPUT ; USE SIGNAL ;  PORT LAYER M3 ; RECT 19.25 3.00 19.75 3.50 ; END  END BWEBMA[23]
  PIN BWEBMA[24] DIRECTION INPUT ; USE SIGNAL ;  PORT LAYER M3 ; RECT 20.00 3.00 20.50 3.50 ; END  END BWEBMA[24]
  PIN BWEBMA[25] DIRECTION INPUT ; USE SIGNAL ;  PORT LAYER M3 ; RECT 20.75 3.00 21.25 3.50 ; END  END BWEBMA[25]
  PIN BWEBMA[26] DIRECTION INPUT ; USE SIGNAL ;  PORT LAYER M3 ; RECT 21.50 3.00 22.00 3.50 ; END  END BWEBMA[26]
  PIN BWEBMA[27] DIRECTION INPUT ; USE SIGNAL ;  PORT LAYER M3 ; RECT 22.25 3.00 22.75 3.50 ; END  END BWEBMA[27]
  PIN BWEBMA[28] DIRECTION INPUT ; USE SIGNAL ;  PORT LAYER M3 ; RECT 23.00 3.00 23.50 3.50 ; END  END BWEBMA[28]
  PIN BWEBMA[29] DIRECTION INPUT ; USE SIGNAL ;  PORT LAYER M3 ; RECT 23.75 3.00 24.25 3.50 ; END  END BWEBMA[29]
  PIN BWEBMA[30] DIRECTION INPUT ; USE SIGNAL ;  PORT LAYER M3 ; RECT 24.50 3.00 25.00 3.50 ; END  END BWEBMA[30]
  PIN BWEBMA[31] DIRECTION INPUT ; USE SIGNAL ;  PORT LAYER M3 ; RECT 25.25 3.00 25.75 3.50 ; END  END BWEBMA[31]

  # BWEBMB[31:0] on south side (y=4.00–4.50), starting x=28.00, step 0.75
  PIN BWEBMB[0]  DIRECTION INPUT ; USE SIGNAL ;  PORT LAYER M3 ; RECT 28.00 4.00 28.50 4.50 ; END  END BWEBMB[0]
  PIN BWEBMB[1]  DIRECTION INPUT ; USE SIGNAL ;  PORT LAYER M3 ; RECT 28.75 4.00 29.25 4.50 ; END  END BWEBMB[1]
  PIN BWEBMB[2]  DIRECTION INPUT ; USE SIGNAL ;  PORT LAYER M3 ; RECT 29.50 4.00 30.00 4.50 ; END  END BWEBMB[2]
  PIN BWEBMB[3]  DIRECTION INPUT ; USE SIGNAL ;  PORT LAYER M3 ; RECT 30.25 4.00 30.75 4.50 ; END  END BWEBMB[3]
  PIN BWEBMB[4]  DIRECTION INPUT ; USE SIGNAL ;  PORT LAYER M3 ; RECT 31.00 4.00 31.50 4.50 ; END  END BWEBMB[4]
  PIN BWEBMB[5]  DIRECTION INPUT ; USE SIGNAL ;  PORT LAYER M3 ; RECT 31.75 4.00 32.25 4.50 ; END  END BWEBMB[5]
  PIN BWEBMB[6]  DIRECTION INPUT ; USE SIGNAL ;  PORT LAYER M3 ; RECT 32.50 4.00 33.00 4.50 ; END  END BWEBMB[6]
  PIN BWEBMB[7]  DIRECTION INPUT ; USE SIGNAL ;  PORT LAYER M3 ; RECT 33.25 4.00 33.75 4.50 ; END  END BWEBMB[7]
  PIN BWEBMB[8]  DIRECTION INPUT ; USE SIGNAL ;  PORT LAYER M3 ; RECT 34.00 4.00 34.50 4.50 ; END  END BWEBMB[8]
  PIN BWEBMB[9]  DIRECTION INPUT ; USE SIGNAL ;  PORT LAYER M3 ; RECT 34.75 4.00 35.25 4.50 ; END  END BWEBMB[9]
  PIN BWEBMB[10] DIRECTION INPUT ; USE SIGNAL ;  PORT LAYER M3 ; RECT 35.50 4.00 36.00 4.50 ; END  END BWEBMB[10]
  PIN BWEBMB[11] DIRECTION INPUT ; USE SIGNAL ;  PORT LAYER M3 ; RECT 36.25 4.00 36.75 4.50 ; END  END BWEBMB[11]
  PIN BWEBMB[12] DIRECTION INPUT ; USE SIGNAL ;  PORT LAYER M3 ; RECT 37.00 4.00 37.50 4.50 ; END  END BWEBMB[12]
  PIN BWEBMB[13] DIRECTION INPUT ; USE SIGNAL ;  PORT LAYER M3 ; RECT 37.75 4.00 38.25 4.50 ; END  END BWEBMB[13]
  PIN BWEBMB[14] DIRECTION INPUT ; USE SIGNAL ;  PORT LAYER M3 ; RECT 38.50 4.00 39.00 4.50 ; END  END BWEBMB[14]
  PIN BWEBMB[15] DIRECTION INPUT ; USE SIGNAL ;  PORT LAYER M3 ; RECT 39.25 4.00 39.75 4.50 ; END  END BWEBMB[15]
  PIN BWEBMB[16] DIRECTION INPUT ; USE SIGNAL ;  PORT LAYER M3 ; RECT 40.00 4.00 40.50 4.50 ; END  END BWEBMB[16]
  PIN BWEBMB[17] DIRECTION INPUT ; USE SIGNAL ;  PORT LAYER M3 ; RECT 40.75 4.00 41.25 4.50 ; END  END BWEBMB[17]
  PIN BWEBMB[18] DIRECTION INPUT ; USE SIGNAL ;  PORT LAYER M3 ; RECT 41.50 4.00 42.00 4.50 ; END  END BWEBMB[18]
  PIN BWEBMB[19] DIRECTION INPUT ; USE SIGNAL ;  PORT LAYER M3 ; RECT 42.25 4.00 42.75 4.50 ; END  END BWEBMB[19]
  PIN BWEBMB[20] DIRECTION INPUT ; USE SIGNAL ;  PORT LAYER M3 ; RECT 43.00 4.00 43.50 4.50 ; END  END BWEBMB[20]
  PIN BWEBMB[21] DIRECTION INPUT ; USE SIGNAL ;  PORT LAYER M3 ; RECT 43.75 4.00 44.25 4.50 ; END  END BWEBMB[21]
  PIN BWEBMB[22] DIRECTION INPUT ; USE SIGNAL ;  PORT LAYER M3 ; RECT 44.50 4.00 45.00 4.50 ; END  END BWEBMB[22]
  PIN BWEBMB[23] DIRECTION INPUT ; USE SIGNAL ;  PORT LAYER M3 ; RECT 45.25 4.00 45.75 4.50 ; END  END BWEBMB[23]
  PIN BWEBMB[24] DIRECTION INPUT ; USE SIGNAL ;  PORT LAYER M3 ; RECT 46.00 4.00 46.50 4.50 ; END  END BWEBMB[24]
  PIN BWEBMB[25] DIRECTION INPUT ; USE SIGNAL ;  PORT LAYER M3 ; RECT 46.75 4.00 47.25 4.50 ; END  END BWEBMB[25]
  PIN BWEBMB[26] DIRECTION INPUT ; USE SIGNAL ;  PORT LAYER M3 ; RECT 47.50 4.00 48.00 4.50 ; END  END BWEBMB[26]
  PIN BWEBMB[27] DIRECTION INPUT ; USE SIGNAL ;  PORT LAYER M3 ; RECT 48.25 4.00 48.75 4.50 ; END  END BWEBMB[27]
  PIN BWEBMB[28] DIRECTION INPUT ; USE SIGNAL ;  PORT LAYER M3 ; RECT 49.00 4.00 49.50 4.50 ; END  END BWEBMB[28]
  PIN BWEBMB[29] DIRECTION INPUT ; USE SIGNAL ;  PORT LAYER M3 ; RECT 49.75 4.00 50.25 4.50 ; END  END BWEBMB[29]
  PIN BWEBMB[30] DIRECTION INPUT ; USE SIGNAL ;  PORT LAYER M3 ; RECT 50.50 4.00 51.00 4.50 ; END  END BWEBMB[30]
  PIN BWEBMB[31] DIRECTION INPUT ; USE SIGNAL ;  PORT LAYER M3 ; RECT 51.25 4.00 51.75 4.50 ; END  END BWEBMB[31]

  # Data output A (QA[31:0]) on south edge
  PIN QA[0] DIRECTION OUTPUT ; USE SIGNAL ;  PORT LAYER M3 ; RECT  8.00 0.00  8.50 0.50 ; END  END QA[0]
  PIN QA[1] DIRECTION OUTPUT ; USE SIGNAL ;  PORT LAYER M3 ; RECT  8.75 0.00  9.25 0.50 ; END  END QA[1]
  PIN QA[2] DIRECTION OUTPUT ; USE SIGNAL ;  PORT LAYER M3 ; RECT  9.50 0.00 10.00 0.50 ; END  END QA[2]
  PIN QA[3] DIRECTION OUTPUT ; USE SIGNAL ;  PORT LAYER M3 ; RECT 10.25 0.00 10.75 0.50 ; END  END QA[3]
  PIN QA[4] DIRECTION OUTPUT ; USE SIGNAL ;  PORT LAYER M3 ; RECT 11.00 0.00 11.50 0.50 ; END  END QA[4]
  PIN QA[5] DIRECTION OUTPUT ; USE SIGNAL ;  PORT LAYER M3 ; RECT 11.75 0.00 12.25 0.50 ; END  END QA[5]
  PIN QA[6] DIRECTION OUTPUT ; USE SIGNAL ;  PORT LAYER M3 ; RECT 12.50 0.00 13.00 0.50 ; END  END QA[6]
  PIN QA[7] DIRECTION OUTPUT ; USE SIGNAL ;  PORT LAYER M3 ; RECT 13.25 0.00 13.75 0.50 ; END  END QA[7]
  PIN QA[8] DIRECTION OUTPUT ; USE SIGNAL ;  PORT LAYER M3 ; RECT 14.00 0.00 14.50 0.50 ; END  END QA[8]
  PIN QA[9] DIRECTION OUTPUT ; USE SIGNAL ;  PORT LAYER M3 ; RECT 14.75 0.00 15.25 0.50 ; END  END QA[9]
  PIN QA[10] DIRECTION OUTPUT ; USE SIGNAL ; PORT LAYER M3 ; RECT 15.50 0.00 16.00 0.50 ; END  END QA[10]
  PIN QA[11] DIRECTION OUTPUT ; USE SIGNAL ; PORT LAYER M3 ; RECT 16.25 0.00 16.75 0.50 ; END  END QA[11]
  PIN QA[12] DIRECTION OUTPUT ; USE SIGNAL ; PORT LAYER M3 ; RECT 17.00 0.00 17.50 0.50 ; END  END QA[12]
  PIN QA[13] DIRECTION OUTPUT ; USE SIGNAL ; PORT LAYER M3 ; RECT 17.75 0.00 18.25 0.50 ; END  END QA[13]
  PIN QA[14] DIRECTION OUTPUT ; USE SIGNAL ; PORT LAYER M3 ; RECT 18.50 0.00 19.00 0.50 ; END  END QA[14]
  PIN QA[15] DIRECTION OUTPUT ; USE SIGNAL ; PORT LAYER M3 ; RECT 19.25 0.00 19.75 0.50 ; END  END QA[15]
  PIN QA[16] DIRECTION OUTPUT ; USE SIGNAL ; PORT LAYER M3 ; RECT 20.00 0.00 20.50 0.50 ; END  END QA[16]
  PIN QA[17] DIRECTION OUTPUT ; USE SIGNAL ; PORT LAYER M3 ; RECT 20.75 0.00 21.25 0.50 ; END  END QA[17]
  PIN QA[18] DIRECTION OUTPUT ; USE SIGNAL ; PORT LAYER M3 ; RECT 21.50 0.00 22.00 0.50 ; END  END QA[18]
  PIN QA[19] DIRECTION OUTPUT ; USE SIGNAL ; PORT LAYER M3 ; RECT 22.25 0.00 22.75 0.50 ; END  END QA[19]
  PIN QA[20] DIRECTION OUTPUT ; USE SIGNAL ; PORT LAYER M3 ; RECT 23.00 0.00 23.50 0.50 ; END  END QA[20]
  PIN QA[21] DIRECTION OUTPUT ; USE SIGNAL ; PORT LAYER M3 ; RECT 23.75 0.00 24.25 0.50 ; END  END QA[21]
  PIN QA[22] DIRECTION OUTPUT ; USE SIGNAL ; PORT LAYER M3 ; RECT 24.50 0.00 25.00 0.50 ; END  END QA[22]
  PIN QA[23] DIRECTION OUTPUT ; USE SIGNAL ; PORT LAYER M3 ; RECT 25.25 0.00 25.75 0.50 ; END  END QA[23]
  PIN QA[24] DIRECTION OUTPUT ; USE SIGNAL ; PORT LAYER M3 ; RECT 26.00 0.00 26.50 0.50 ; END  END QA[24]
  PIN QA[25] DIRECTION OUTPUT ; USE SIGNAL ; PORT LAYER M3 ; RECT 26.75 0.00 27.25 0.50 ; END  END QA[25]
  PIN QA[26] DIRECTION OUTPUT ; USE SIGNAL ; PORT LAYER M3 ; RECT 27.50 0.00 28.00 0.50 ; END  END QA[26]
  PIN QA[27] DIRECTION OUTPUT ; USE SIGNAL ; PORT LAYER M3 ; RECT 28.25 0.00 28.75 0.50 ; END  END QA[27]
  PIN QA[28] DIRECTION OUTPUT ; USE SIGNAL ; PORT LAYER M3 ; RECT 29.00 0.00 29.50 0.50 ; END  END QA[28]
  PIN QA[29] DIRECTION OUTPUT ; USE SIGNAL ; PORT LAYER M3 ; RECT 29.75 0.00 30.25 0.50 ; END  END QA[29]
  PIN QA[30] DIRECTION OUTPUT ; USE SIGNAL ; PORT LAYER M3 ; RECT 30.50 0.00 31.00 0.50 ; END  END QA[30]
  PIN QA[31] DIRECTION OUTPUT ; USE SIGNAL ; PORT LAYER M3 ; RECT 31.25 0.00 31.75 0.50 ; END  END QA[31]

  # Data output B (QB[31:0]) on south edge
  PIN QB[0] DIRECTION OUTPUT ; USE SIGNAL ;  PORT LAYER M3 ; RECT 36.00 0.00 36.50 0.50 ; END  END QB[0]
  PIN QB[1] DIRECTION OUTPUT ; USE SIGNAL ;  PORT LAYER M3 ; RECT 36.75 0.00 37.25 0.50 ; END  END QB[1]
  PIN QB[2] DIRECTION OUTPUT ; USE SIGNAL ;  PORT LAYER M3 ; RECT 37.50 0.00 38.00 0.50 ; END  END QB[2]
  PIN QB[3] DIRECTION OUTPUT ; USE SIGNAL ;  PORT LAYER M3 ; RECT 38.25 0.00 38.75 0.50 ; END  END QB[3]
  PIN QB[4] DIRECTION OUTPUT ; USE SIGNAL ;  PORT LAYER M3 ; RECT 39.00 0.00 39.50 0.50 ; END  END QB[4]
  PIN QB[5] DIRECTION OUTPUT ; USE SIGNAL ;  PORT LAYER M3 ; RECT 39.75 0.00 40.25 0.50 ; END  END QB[5]
  PIN QB[6] DIRECTION OUTPUT ; USE SIGNAL ;  PORT LAYER M3 ; RECT 40.50 0.00 41.00 0.50 ; END  END QB[6]
  PIN QB[7] DIRECTION OUTPUT ; USE SIGNAL ;  PORT LAYER M3 ; RECT 41.25 0.00 41.75 0.50 ; END  END QB[7]
  PIN QB[8] DIRECTION OUTPUT ; USE SIGNAL ;  PORT LAYER M3 ; RECT 42.00 0.00 42.50 0.50 ; END  END QB[8]
  PIN QB[9] DIRECTION OUTPUT ; USE SIGNAL ;  PORT LAYER M3 ; RECT 42.75 0.00 43.25 0.50 ; END  END QB[9]
  PIN QB[10] DIRECTION OUTPUT ; USE SIGNAL ; PORT LAYER M3 ; RECT 43.50 0.00 44.00 0.50 ; END  END QB[10]
  PIN QB[11] DIRECTION OUTPUT ; USE SIGNAL ; PORT LAYER M3 ; RECT 44.25 0.00 44.75 0.50 ; END  END QB[11]
  PIN QB[12] DIRECTION OUTPUT ; USE SIGNAL ; PORT LAYER M3 ; RECT 45.00 0.00 45.50 0.50 ; END  END QB[12]
  PIN QB[13] DIRECTION OUTPUT ; USE SIGNAL ; PORT LAYER M3 ; RECT 45.75 0.00 46.25 0.50 ; END  END QB[13]
  PIN QB[14] DIRECTION OUTPUT ; USE SIGNAL ; PORT LAYER M3 ; RECT 46.50 0.00 47.00 0.50 ; END  END QB[14]
  PIN QB[15] DIRECTION OUTPUT ; USE SIGNAL ; PORT LAYER M3 ; RECT 47.25 0.00 47.75 0.50 ; END  END QB[15]
  PIN QB[16] DIRECTION OUTPUT ; USE SIGNAL ; PORT LAYER M3 ; RECT 48.00 0.00 48.50 0.50 ; END  END QB[16]
  PIN QB[17] DIRECTION OUTPUT ; USE SIGNAL ; PORT LAYER M3 ; RECT 48.75 0.00 49.25 0.50 ; END  END QB[17]
  PIN QB[18] DIRECTION OUTPUT ; USE SIGNAL ; PORT LAYER M3 ; RECT 49.50 0.00 50.00 0.50 ; END  END QB[18]
  PIN QB[19] DIRECTION OUTPUT ; USE SIGNAL ; PORT LAYER M3 ; RECT 50.25 0.00 50.75 0.50 ; END  END QB[19]
  PIN QB[20] DIRECTION OUTPUT ; USE SIGNAL ; PORT LAYER M3 ; RECT 51.00 0.00 51.50 0.50 ; END  END QB[20]
  PIN QB[21] DIRECTION OUTPUT ; USE SIGNAL ; PORT LAYER M3 ; RECT 51.75 0.00 52.25 0.50 ; END  END QB[21]
  PIN QB[22] DIRECTION OUTPUT ; USE SIGNAL ; PORT LAYER M3 ; RECT 52.50 0.00 53.00 0.50 ; END  END QB[22]
  PIN QB[23] DIRECTION OUTPUT ; USE SIGNAL ; PORT LAYER M3 ; RECT 53.25 0.00 53.75 0.50 ; END  END QB[23]
  PIN QB[24] DIRECTION OUTPUT ; USE SIGNAL ; PORT LAYER M3 ; RECT 54.00 0.00 54.50 0.50 ; END  END QB[24]
  PIN QB[25] DIRECTION OUTPUT ; USE SIGNAL ; PORT LAYER M3 ; RECT 54.75 0.00 55.25 0.50 ; END  END QB[25]
  PIN QB[26] DIRECTION OUTPUT ; USE SIGNAL ; PORT LAYER M3 ; RECT 55.50 0.00 56.00 0.50 ; END  END QB[26]
  PIN QB[27] DIRECTION OUTPUT ; USE SIGNAL ; PORT LAYER M3 ; RECT 56.25 0.00 56.75 0.50 ; END  END QB[27]
  PIN QB[28] DIRECTION OUTPUT ; USE SIGNAL ; PORT LAYER M3 ; RECT 57.00 0.00 57.50 0.50 ; END  END QB[28]
  PIN QB[29] DIRECTION OUTPUT ; USE SIGNAL ; PORT LAYER M3 ; RECT 57.75 0.00 58.25 0.50 ; END  END QB[29]
  PIN QB[30] DIRECTION OUTPUT ; USE SIGNAL ; PORT LAYER M3 ; RECT 58.50 0.00 59.00 0.50 ; END  END QB[30]
  PIN QB[31] DIRECTION OUTPUT ; USE SIGNAL ; PORT LAYER M3 ; RECT 59.25 0.00 59.75 0.50 ; END  END QB[31]

  # ------- Obstructions (block routing through macro body) -------
  OBS
    LAYER M1 ; RECT 0 0 60 100 ;
    LAYER M2 ; RECT 0 0 60 100 ;
    LAYER M3 ; RECT 0 0 60 100 ;
    LAYER M4 ; RECT 0 0 60 100 ;
    LAYER M5 ; RECT 0 0 60 100 ;
  END

END TSDN40LPA512X32M4F
END LIBRARY

